VERSION 5.7 ;
  NOWIREEXTENSIONATPIN ON ;
  DIVIDERCHAR "/" ;
  BUSBITCHARS "[]" ;
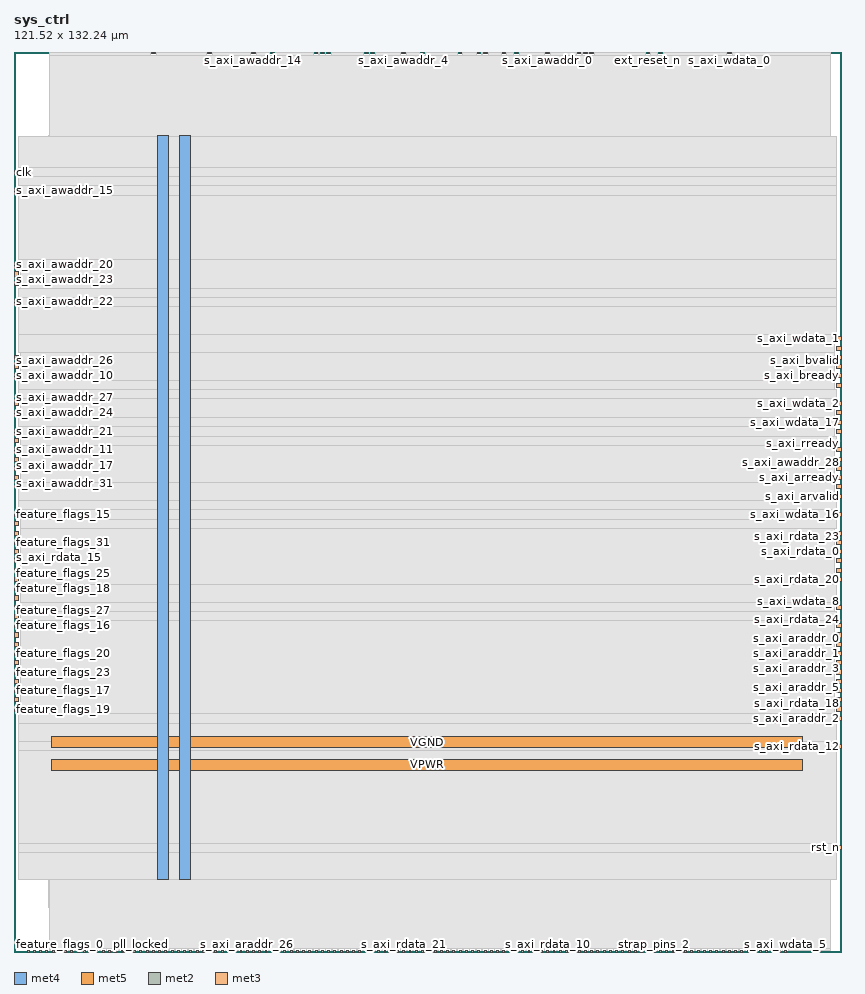
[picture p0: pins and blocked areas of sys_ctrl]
MACRO sys_ctrl
  CLASS BLOCK ;
  FOREIGN sys_ctrl ;
  ORIGIN 0.000 0.000 ;
  SIZE 121.520 BY 132.240 ;
  PIN VGND
    DIRECTION INOUT ;
    USE GROUND ;
    PORT
      LAYER met4 ;
        RECT 24.340 10.640 25.940 119.920 ;
    END
    PORT
      LAYER met5 ;
        RECT 5.520 30.030 115.920 31.630 ;
    END
  END VGND
  PIN VPWR
    DIRECTION INOUT ;
    USE POWER ;
    PORT
      LAYER met4 ;
        RECT 21.040 10.640 22.640 119.920 ;
    END
    PORT
      LAYER met5 ;
        RECT 5.520 26.730 115.920 28.330 ;
    END
  END VPWR
  PIN boot_mode_0
    DIRECTION INPUT ;
    USE SIGNAL ;
    PORT
      LAYER met2 ;
        RECT 2.850 0.000 3.130 0.280 ;
    END
  END boot_mode_0
  PIN boot_mode_1
    DIRECTION INPUT ;
    USE SIGNAL ;
    PORT
      LAYER met2 ;
        RECT 3.770 0.000 4.050 0.280 ;
    END
  END boot_mode_1
  PIN clk
    DIRECTION INPUT ;
    USE SIGNAL ;
    ANTENNAGATEAREA 1.286700 ;
    ANTENNADIFFAREA 0.434700 ;
    PORT
      LAYER met3 ;
        RECT 0.000 114.280 0.600 114.880 ;
    END
  END clk
  PIN ext_reset_n
    DIRECTION INPUT ;
    USE SIGNAL ;
    ANTENNAGATEAREA 0.647700 ;
    ANTENNADIFFAREA 0.434700 ;
    PORT
      LAYER met2 ;
        RECT 93.010 131.960 93.290 132.240 ;
    END
  END ext_reset_n
  PIN feature_flags_0
    DIRECTION OUTPUT ;
    USE SIGNAL ;
    PORT
      LAYER met2 ;
        RECT 4.690 0.000 4.970 0.280 ;
    END
  END feature_flags_0
  PIN feature_flags_1
    DIRECTION OUTPUT ;
    USE SIGNAL ;
    PORT
      LAYER met2 ;
        RECT 5.610 0.000 5.890 0.280 ;
    END
  END feature_flags_1
  PIN feature_flags_10
    DIRECTION OUTPUT ;
    USE SIGNAL ;
    PORT
      LAYER met2 ;
        RECT 6.530 0.000 6.810 0.280 ;
    END
  END feature_flags_10
  PIN feature_flags_11
    DIRECTION OUTPUT ;
    USE SIGNAL ;
    PORT
      LAYER met2 ;
        RECT 7.450 0.000 7.730 0.280 ;
    END
  END feature_flags_11
  PIN feature_flags_12
    DIRECTION OUTPUT ;
    USE SIGNAL ;
    PORT
      LAYER met2 ;
        RECT 8.370 0.000 8.650 0.280 ;
    END
  END feature_flags_12
  PIN feature_flags_13
    DIRECTION OUTPUT ;
    USE SIGNAL ;
    PORT
      LAYER met2 ;
        RECT 9.290 0.000 9.570 0.280 ;
    END
  END feature_flags_13
  PIN feature_flags_14
    DIRECTION OUTPUT ;
    USE SIGNAL ;
    PORT
      LAYER met2 ;
        RECT 10.210 0.000 10.490 0.280 ;
    END
  END feature_flags_14
  PIN feature_flags_15
    DIRECTION OUTPUT ;
    USE SIGNAL ;
    ANTENNAGATEAREA 0.434700 ;
    ANTENNADIFFAREA 0.775300 ;
    PORT
      LAYER met3 ;
        RECT 0.000 63.960 0.600 64.560 ;
    END
  END feature_flags_15
  PIN feature_flags_16
    DIRECTION OUTPUT ;
    USE SIGNAL ;
    ANTENNAGATEAREA 0.434700 ;
    ANTENNADIFFAREA 0.775300 ;
    PORT
      LAYER met3 ;
        RECT 0.000 47.640 0.600 48.240 ;
    END
  END feature_flags_16
  PIN feature_flags_17
    DIRECTION OUTPUT ;
    USE SIGNAL ;
    ANTENNAGATEAREA 0.434700 ;
    ANTENNADIFFAREA 0.775300 ;
    PORT
      LAYER met3 ;
        RECT 0.000 38.120 0.600 38.720 ;
    END
  END feature_flags_17
  PIN feature_flags_18
    DIRECTION OUTPUT ;
    USE SIGNAL ;
    ANTENNAGATEAREA 0.434700 ;
    ANTENNADIFFAREA 0.775300 ;
    PORT
      LAYER met3 ;
        RECT 0.000 53.080 0.600 53.680 ;
    END
  END feature_flags_18
  PIN feature_flags_19
    DIRECTION OUTPUT ;
    USE SIGNAL ;
    ANTENNAGATEAREA 0.434700 ;
    ANTENNADIFFAREA 0.775300 ;
    PORT
      LAYER met3 ;
        RECT 0.000 35.400 0.600 36.000 ;
    END
  END feature_flags_19
  PIN feature_flags_2
    DIRECTION OUTPUT ;
    USE SIGNAL ;
    PORT
      LAYER met2 ;
        RECT 11.130 0.000 11.410 0.280 ;
    END
  END feature_flags_2
  PIN feature_flags_20
    DIRECTION OUTPUT ;
    USE SIGNAL ;
    ANTENNAGATEAREA 0.434700 ;
    ANTENNADIFFAREA 0.775300 ;
    PORT
      LAYER met3 ;
        RECT 0.000 43.560 0.600 44.160 ;
    END
  END feature_flags_20
  PIN feature_flags_21
    DIRECTION OUTPUT ;
    USE SIGNAL ;
    ANTENNAGATEAREA 0.434700 ;
    ANTENNADIFFAREA 0.775300 ;
    PORT
      LAYER met3 ;
        RECT 0.000 55.800 0.600 56.400 ;
    END
  END feature_flags_21
  PIN feature_flags_22
    DIRECTION OUTPUT ;
    USE SIGNAL ;
    ANTENNAGATEAREA 0.434700 ;
    ANTENNADIFFAREA 0.775300 ;
    PORT
      LAYER met3 ;
        RECT 0.000 46.280 0.600 46.880 ;
    END
  END feature_flags_22
  PIN feature_flags_23
    DIRECTION OUTPUT ;
    USE SIGNAL ;
    ANTENNAGATEAREA 0.434700 ;
    ANTENNADIFFAREA 0.775300 ;
    PORT
      LAYER met3 ;
        RECT 0.000 40.840 0.600 41.440 ;
    END
  END feature_flags_23
  PIN feature_flags_24
    DIRECTION OUTPUT ;
    USE SIGNAL ;
    ANTENNAGATEAREA 0.434700 ;
    ANTENNADIFFAREA 0.775300 ;
    PORT
      LAYER met3 ;
        RECT 0.000 57.160 0.600 57.760 ;
    END
  END feature_flags_24
  PIN feature_flags_25
    DIRECTION OUTPUT ;
    USE SIGNAL ;
    ANTENNAGATEAREA 0.434700 ;
    ANTENNADIFFAREA 0.775300 ;
    PORT
      LAYER met3 ;
        RECT 0.000 54.440 0.600 55.040 ;
    END
  END feature_flags_25
  PIN feature_flags_26
    DIRECTION OUTPUT ;
    USE SIGNAL ;
    ANTENNAGATEAREA 0.434700 ;
    ANTENNADIFFAREA 0.775300 ;
    PORT
      LAYER met3 ;
        RECT 0.000 44.920 0.600 45.520 ;
    END
  END feature_flags_26
  PIN feature_flags_27
    DIRECTION OUTPUT ;
    USE SIGNAL ;
    ANTENNAGATEAREA 0.434700 ;
    ANTENNADIFFAREA 0.775300 ;
    PORT
      LAYER met3 ;
        RECT 0.000 49.000 0.600 49.600 ;
    END
  END feature_flags_27
  PIN feature_flags_28
    DIRECTION OUTPUT ;
    USE SIGNAL ;
    ANTENNAGATEAREA 0.434700 ;
    ANTENNADIFFAREA 0.775300 ;
    PORT
      LAYER met3 ;
        RECT 0.000 51.720 0.600 52.320 ;
    END
  END feature_flags_28
  PIN feature_flags_29
    DIRECTION OUTPUT ;
    USE SIGNAL ;
    ANTENNAGATEAREA 0.434700 ;
    ANTENNADIFFAREA 0.775300 ;
    PORT
      LAYER met3 ;
        RECT 0.000 39.480 0.600 40.080 ;
    END
  END feature_flags_29
  PIN feature_flags_3
    DIRECTION OUTPUT ;
    USE SIGNAL ;
    PORT
      LAYER met2 ;
        RECT 12.050 0.000 12.330 0.280 ;
    END
  END feature_flags_3
  PIN feature_flags_30
    DIRECTION OUTPUT ;
    USE SIGNAL ;
    ANTENNAGATEAREA 0.434700 ;
    ANTENNADIFFAREA 0.775300 ;
    PORT
      LAYER met3 ;
        RECT 0.000 42.200 0.600 42.800 ;
    END
  END feature_flags_30
  PIN feature_flags_31
    DIRECTION OUTPUT ;
    USE SIGNAL ;
    ANTENNAGATEAREA 0.434700 ;
    ANTENNADIFFAREA 0.775300 ;
    PORT
      LAYER met3 ;
        RECT 0.000 59.880 0.600 60.480 ;
    END
  END feature_flags_31
  PIN feature_flags_4
    DIRECTION OUTPUT ;
    USE SIGNAL ;
    PORT
      LAYER met2 ;
        RECT 12.970 0.000 13.250 0.280 ;
    END
  END feature_flags_4
  PIN feature_flags_5
    DIRECTION OUTPUT ;
    USE SIGNAL ;
    PORT
      LAYER met2 ;
        RECT 13.890 0.000 14.170 0.280 ;
    END
  END feature_flags_5
  PIN feature_flags_6
    DIRECTION OUTPUT ;
    USE SIGNAL ;
    PORT
      LAYER met2 ;
        RECT 14.810 0.000 15.090 0.280 ;
    END
  END feature_flags_6
  PIN feature_flags_7
    DIRECTION OUTPUT ;
    USE SIGNAL ;
    PORT
      LAYER met2 ;
        RECT 15.730 0.000 16.010 0.280 ;
    END
  END feature_flags_7
  PIN feature_flags_8
    DIRECTION OUTPUT ;
    USE SIGNAL ;
    PORT
      LAYER met2 ;
        RECT 16.650 0.000 16.930 0.280 ;
    END
  END feature_flags_8
  PIN feature_flags_9
    DIRECTION OUTPUT ;
    USE SIGNAL ;
    PORT
      LAYER met2 ;
        RECT 17.570 0.000 17.850 0.280 ;
    END
  END feature_flags_9
  PIN lockup_reset
    DIRECTION INPUT ;
    USE SIGNAL ;
    ANTENNAGATEAREA 0.647700 ;
    ANTENNADIFFAREA 0.434700 ;
    PORT
      LAYER met2 ;
        RECT 94.850 131.960 95.130 132.240 ;
    END
  END lockup_reset
  PIN pll_locked
    DIRECTION INPUT ;
    USE SIGNAL ;
    PORT
      LAYER met2 ;
        RECT 18.490 0.000 18.770 0.280 ;
    END
  END pll_locked
  PIN ref_clk_ok
    DIRECTION INPUT ;
    USE SIGNAL ;
    PORT
      LAYER met2 ;
        RECT 19.410 0.000 19.690 0.280 ;
    END
  END ref_clk_ok
  PIN rst_n
    DIRECTION INPUT ;
    USE SIGNAL ;
    ANTENNAGATEAREA 0.647700 ;
    ANTENNADIFFAREA 0.434700 ;
    PORT
      LAYER met3 ;
        RECT 120.920 15.000 121.520 15.600 ;
    END
  END rst_n
  PIN s_axi_araddr_0
    DIRECTION INPUT ;
    USE SIGNAL ;
    ANTENNAGATEAREA 0.647700 ;
    ANTENNADIFFAREA 0.434700 ;
    PORT
      LAYER met3 ;
        RECT 120.920 44.920 121.520 45.520 ;
    END
  END s_axi_araddr_0
  PIN s_axi_araddr_1
    DIRECTION INPUT ;
    USE SIGNAL ;
    ANTENNAGATEAREA 0.647700 ;
    ANTENNADIFFAREA 0.434700 ;
    PORT
      LAYER met3 ;
        RECT 120.920 43.560 121.520 44.160 ;
    END
  END s_axi_araddr_1
  PIN s_axi_araddr_10
    DIRECTION INPUT ;
    USE SIGNAL ;
    PORT
      LAYER met2 ;
        RECT 20.330 0.000 20.610 0.280 ;
    END
  END s_axi_araddr_10
  PIN s_axi_araddr_11
    DIRECTION INPUT ;
    USE SIGNAL ;
    PORT
      LAYER met2 ;
        RECT 21.250 0.000 21.530 0.280 ;
    END
  END s_axi_araddr_11
  PIN s_axi_araddr_12
    DIRECTION INPUT ;
    USE SIGNAL ;
    PORT
      LAYER met2 ;
        RECT 22.170 0.000 22.450 0.280 ;
    END
  END s_axi_araddr_12
  PIN s_axi_araddr_13
    DIRECTION INPUT ;
    USE SIGNAL ;
    PORT
      LAYER met2 ;
        RECT 23.090 0.000 23.370 0.280 ;
    END
  END s_axi_araddr_13
  PIN s_axi_araddr_14
    DIRECTION INPUT ;
    USE SIGNAL ;
    PORT
      LAYER met2 ;
        RECT 24.010 0.000 24.290 0.280 ;
    END
  END s_axi_araddr_14
  PIN s_axi_araddr_15
    DIRECTION INPUT ;
    USE SIGNAL ;
    PORT
      LAYER met2 ;
        RECT 74.610 0.000 74.890 0.280 ;
    END
  END s_axi_araddr_15
  PIN s_axi_araddr_16
    DIRECTION INPUT ;
    USE SIGNAL ;
    PORT
      LAYER met2 ;
        RECT 24.930 0.000 25.210 0.280 ;
    END
  END s_axi_araddr_16
  PIN s_axi_araddr_17
    DIRECTION INPUT ;
    USE SIGNAL ;
    PORT
      LAYER met2 ;
        RECT 25.850 0.000 26.130 0.280 ;
    END
  END s_axi_araddr_17
  PIN s_axi_araddr_18
    DIRECTION INPUT ;
    USE SIGNAL ;
    PORT
      LAYER met2 ;
        RECT 26.770 0.000 27.050 0.280 ;
    END
  END s_axi_araddr_18
  PIN s_axi_araddr_19
    DIRECTION INPUT ;
    USE SIGNAL ;
    PORT
      LAYER met2 ;
        RECT 27.690 0.000 27.970 0.280 ;
    END
  END s_axi_araddr_19
  PIN s_axi_araddr_2
    DIRECTION INPUT ;
    USE SIGNAL ;
    ANTENNAGATEAREA 0.647700 ;
    ANTENNADIFFAREA 0.434700 ;
    PORT
      LAYER met3 ;
        RECT 120.920 34.040 121.520 34.640 ;
    END
  END s_axi_araddr_2
  PIN s_axi_araddr_20
    DIRECTION INPUT ;
    USE SIGNAL ;
    PORT
      LAYER met2 ;
        RECT 28.610 0.000 28.890 0.280 ;
    END
  END s_axi_araddr_20
  PIN s_axi_araddr_21
    DIRECTION INPUT ;
    USE SIGNAL ;
    PORT
      LAYER met2 ;
        RECT 29.530 0.000 29.810 0.280 ;
    END
  END s_axi_araddr_21
  PIN s_axi_araddr_22
    DIRECTION INPUT ;
    USE SIGNAL ;
    PORT
      LAYER met2 ;
        RECT 30.450 0.000 30.730 0.280 ;
    END
  END s_axi_araddr_22
  PIN s_axi_araddr_23
    DIRECTION INPUT ;
    USE SIGNAL ;
    PORT
      LAYER met2 ;
        RECT 31.370 0.000 31.650 0.280 ;
    END
  END s_axi_araddr_23
  PIN s_axi_araddr_24
    DIRECTION INPUT ;
    USE SIGNAL ;
    PORT
      LAYER met2 ;
        RECT 32.290 0.000 32.570 0.280 ;
    END
  END s_axi_araddr_24
  PIN s_axi_araddr_25
    DIRECTION INPUT ;
    USE SIGNAL ;
    PORT
      LAYER met2 ;
        RECT 33.210 0.000 33.490 0.280 ;
    END
  END s_axi_araddr_25
  PIN s_axi_araddr_26
    DIRECTION INPUT ;
    USE SIGNAL ;
    PORT
      LAYER met2 ;
        RECT 34.130 0.000 34.410 0.280 ;
    END
  END s_axi_araddr_26
  PIN s_axi_araddr_27
    DIRECTION INPUT ;
    USE SIGNAL ;
    PORT
      LAYER met2 ;
        RECT 35.050 0.000 35.330 0.280 ;
    END
  END s_axi_araddr_27
  PIN s_axi_araddr_28
    DIRECTION INPUT ;
    USE SIGNAL ;
    PORT
      LAYER met2 ;
        RECT 35.970 0.000 36.250 0.280 ;
    END
  END s_axi_araddr_28
  PIN s_axi_araddr_29
    DIRECTION INPUT ;
    USE SIGNAL ;
    PORT
      LAYER met2 ;
        RECT 36.890 0.000 37.170 0.280 ;
    END
  END s_axi_araddr_29
  PIN s_axi_araddr_3
    DIRECTION INPUT ;
    USE SIGNAL ;
    ANTENNAGATEAREA 0.647700 ;
    ANTENNADIFFAREA 0.434700 ;
    PORT
      LAYER met3 ;
        RECT 120.920 42.200 121.520 42.800 ;
    END
  END s_axi_araddr_3
  PIN s_axi_araddr_30
    DIRECTION INPUT ;
    USE SIGNAL ;
    PORT
      LAYER met2 ;
        RECT 37.810 0.000 38.090 0.280 ;
    END
  END s_axi_araddr_30
  PIN s_axi_araddr_31
    DIRECTION INPUT ;
    USE SIGNAL ;
    PORT
      LAYER met2 ;
        RECT 38.730 0.000 39.010 0.280 ;
    END
  END s_axi_araddr_31
  PIN s_axi_araddr_4
    DIRECTION INPUT ;
    USE SIGNAL ;
    ANTENNAGATEAREA 0.647700 ;
    ANTENNADIFFAREA 0.434700 ;
    PORT
      LAYER met3 ;
        RECT 120.920 40.840 121.520 41.440 ;
    END
  END s_axi_araddr_4
  PIN s_axi_araddr_5
    DIRECTION INPUT ;
    USE SIGNAL ;
    ANTENNAGATEAREA 0.647700 ;
    ANTENNADIFFAREA 0.434700 ;
    PORT
      LAYER met3 ;
        RECT 120.920 39.480 121.520 40.080 ;
    END
  END s_axi_araddr_5
  PIN s_axi_araddr_6
    DIRECTION INPUT ;
    USE SIGNAL ;
    ANTENNAGATEAREA 0.647700 ;
    ANTENNADIFFAREA 0.434700 ;
    PORT
      LAYER met3 ;
        RECT 120.920 38.120 121.520 38.720 ;
    END
  END s_axi_araddr_6
  PIN s_axi_araddr_7
    DIRECTION INPUT ;
    USE SIGNAL ;
    ANTENNAGATEAREA 0.647700 ;
    ANTENNADIFFAREA 0.434700 ;
    PORT
      LAYER met3 ;
        RECT 120.920 36.760 121.520 37.360 ;
    END
  END s_axi_araddr_7
  PIN s_axi_araddr_8
    DIRECTION INPUT ;
    USE SIGNAL ;
    PORT
      LAYER met2 ;
        RECT 39.650 0.000 39.930 0.280 ;
    END
  END s_axi_araddr_8
  PIN s_axi_araddr_9
    DIRECTION INPUT ;
    USE SIGNAL ;
    PORT
      LAYER met2 ;
        RECT 40.570 0.000 40.850 0.280 ;
    END
  END s_axi_araddr_9
  PIN s_axi_arready
    DIRECTION OUTPUT ;
    USE SIGNAL ;
    ANTENNAGATEAREA 0.434700 ;
    ANTENNADIFFAREA 1.137600 ;
    PORT
      LAYER met3 ;
        RECT 120.920 69.400 121.520 70.000 ;
    END
  END s_axi_arready
  PIN s_axi_arvalid
    DIRECTION INPUT ;
    USE SIGNAL ;
    ANTENNAGATEAREA 0.647700 ;
    ANTENNADIFFAREA 0.434700 ;
    PORT
      LAYER met3 ;
        RECT 120.920 66.680 121.520 67.280 ;
    END
  END s_axi_arvalid
  PIN s_axi_awaddr_0
    DIRECTION INPUT ;
    USE SIGNAL ;
    ANTENNAGATEAREA 0.647700 ;
    ANTENNADIFFAREA 0.434700 ;
    PORT
      LAYER met2 ;
        RECT 78.290 131.960 78.570 132.240 ;
    END
  END s_axi_awaddr_0
  PIN s_axi_awaddr_1
    DIRECTION INPUT ;
    USE SIGNAL ;
    ANTENNAGATEAREA 0.647700 ;
    ANTENNADIFFAREA 0.434700 ;
    PORT
      LAYER met2 ;
        RECT 69.090 131.960 69.370 132.240 ;
    END
  END s_axi_awaddr_1
  PIN s_axi_awaddr_10
    DIRECTION INPUT ;
    USE SIGNAL ;
    ANTENNAGATEAREA 0.647700 ;
    ANTENNADIFFAREA 0.434700 ;
    PORT
      LAYER met3 ;
        RECT 0.000 84.360 0.600 84.960 ;
    END
  END s_axi_awaddr_10
  PIN s_axi_awaddr_11
    DIRECTION INPUT ;
    USE SIGNAL ;
    ANTENNAGATEAREA 0.647700 ;
    ANTENNADIFFAREA 0.434700 ;
    PORT
      LAYER met3 ;
        RECT 0.000 73.480 0.600 74.080 ;
    END
  END s_axi_awaddr_11
  PIN s_axi_awaddr_12
    DIRECTION INPUT ;
    USE SIGNAL ;
    ANTENNAGATEAREA 0.647700 ;
    ANTENNADIFFAREA 0.434700 ;
    PORT
      LAYER met2 ;
        RECT 45.170 131.960 45.450 132.240 ;
    END
  END s_axi_awaddr_12
  PIN s_axi_awaddr_13
    DIRECTION INPUT ;
    USE SIGNAL ;
    ANTENNAGATEAREA 0.647700 ;
    ANTENNADIFFAREA 0.434700 ;
    PORT
      LAYER met2 ;
        RECT 52.530 131.960 52.810 132.240 ;
    END
  END s_axi_awaddr_13
  PIN s_axi_awaddr_14
    DIRECTION INPUT ;
    USE SIGNAL ;
    ANTENNAGATEAREA 0.647700 ;
    ANTENNADIFFAREA 0.434700 ;
    PORT
      LAYER met2 ;
        RECT 35.050 131.960 35.330 132.240 ;
    END
  END s_axi_awaddr_14
  PIN s_axi_awaddr_15
    DIRECTION INPUT ;
    USE SIGNAL ;
    ANTENNAGATEAREA 0.647700 ;
    ANTENNADIFFAREA 0.434700 ;
    PORT
      LAYER met3 ;
        RECT 0.000 111.560 0.600 112.160 ;
    END
  END s_axi_awaddr_15
  PIN s_axi_awaddr_16
    DIRECTION INPUT ;
    USE SIGNAL ;
    ANTENNAGATEAREA 0.647700 ;
    ANTENNADIFFAREA 0.434700 ;
    PORT
      LAYER met2 ;
        RECT 44.250 131.960 44.530 132.240 ;
    END
  END s_axi_awaddr_16
  PIN s_axi_awaddr_17
    DIRECTION INPUT ;
    USE SIGNAL ;
    ANTENNAGATEAREA 0.647700 ;
    ANTENNADIFFAREA 0.434700 ;
    PORT
      LAYER met3 ;
        RECT 0.000 72.120 0.600 72.720 ;
    END
  END s_axi_awaddr_17
  PIN s_axi_awaddr_18
    DIRECTION INPUT ;
    USE SIGNAL ;
    ANTENNAGATEAREA 0.647700 ;
    ANTENNADIFFAREA 0.434700 ;
    PORT
      LAYER met2 ;
        RECT 28.610 131.960 28.890 132.240 ;
    END
  END s_axi_awaddr_18
  PIN s_axi_awaddr_19
    DIRECTION INPUT ;
    USE SIGNAL ;
    ANTENNAGATEAREA 0.647700 ;
    ANTENNADIFFAREA 0.434700 ;
    PORT
      LAYER met2 ;
        RECT 37.810 131.960 38.090 132.240 ;
    END
  END s_axi_awaddr_19
  PIN s_axi_awaddr_2
    DIRECTION INPUT ;
    USE SIGNAL ;
    ANTENNAGATEAREA 0.647700 ;
    ANTENNADIFFAREA 0.434700 ;
    PORT
      LAYER met2 ;
        RECT 73.690 131.960 73.970 132.240 ;
    END
  END s_axi_awaddr_2
  PIN s_axi_awaddr_20
    DIRECTION INPUT ;
    USE SIGNAL ;
    ANTENNAGATEAREA 0.647700 ;
    ANTENNADIFFAREA 0.434700 ;
    PORT
      LAYER met3 ;
        RECT 0.000 100.680 0.600 101.280 ;
    END
  END s_axi_awaddr_20
  PIN s_axi_awaddr_21
    DIRECTION INPUT ;
    USE SIGNAL ;
    ANTENNAGATEAREA 0.647700 ;
    ANTENNADIFFAREA 0.434700 ;
    PORT
      LAYER met3 ;
        RECT 0.000 76.200 0.600 76.800 ;
    END
  END s_axi_awaddr_21
  PIN s_axi_awaddr_22
    DIRECTION INPUT ;
    USE SIGNAL ;
    ANTENNAGATEAREA 0.647700 ;
    ANTENNADIFFAREA 0.434700 ;
    PORT
      LAYER met3 ;
        RECT 0.000 95.240 0.600 95.840 ;
    END
  END s_axi_awaddr_22
  PIN s_axi_awaddr_23
    DIRECTION INPUT ;
    USE SIGNAL ;
    ANTENNAGATEAREA 0.647700 ;
    ANTENNADIFFAREA 0.434700 ;
    PORT
      LAYER met3 ;
        RECT 0.000 99.320 0.600 99.920 ;
    END
  END s_axi_awaddr_23
  PIN s_axi_awaddr_24
    DIRECTION INPUT ;
    USE SIGNAL ;
    ANTENNAGATEAREA 0.647700 ;
    ANTENNADIFFAREA 0.434700 ;
    PORT
      LAYER met3 ;
        RECT 0.000 78.920 0.600 79.520 ;
    END
  END s_axi_awaddr_24
  PIN s_axi_awaddr_25
    DIRECTION INPUT ;
    USE SIGNAL ;
    ANTENNAGATEAREA 0.647700 ;
    ANTENNADIFFAREA 0.434700 ;
    PORT
      LAYER met2 ;
        RECT 20.330 131.960 20.610 132.240 ;
    END
  END s_axi_awaddr_25
  PIN s_axi_awaddr_26
    DIRECTION INPUT ;
    USE SIGNAL ;
    ANTENNAGATEAREA 0.647700 ;
    ANTENNADIFFAREA 0.434700 ;
    PORT
      LAYER met3 ;
        RECT 0.000 85.720 0.600 86.320 ;
    END
  END s_axi_awaddr_26
  PIN s_axi_awaddr_27
    DIRECTION INPUT ;
    USE SIGNAL ;
    ANTENNAGATEAREA 0.647700 ;
    ANTENNADIFFAREA 0.434700 ;
    PORT
      LAYER met3 ;
        RECT 0.000 80.280 0.600 80.880 ;
    END
  END s_axi_awaddr_27
  PIN s_axi_awaddr_28
    DIRECTION INPUT ;
    USE SIGNAL ;
    ANTENNAGATEAREA 0.647700 ;
    ANTENNADIFFAREA 0.434700 ;
    PORT
      LAYER met3 ;
        RECT 120.920 70.760 121.520 71.360 ;
    END
  END s_axi_awaddr_28
  PIN s_axi_awaddr_29
    DIRECTION INPUT ;
    USE SIGNAL ;
    ANTENNAGATEAREA 0.647700 ;
    ANTENNADIFFAREA 0.434700 ;
    PORT
      LAYER met3 ;
        RECT 0.000 70.760 0.600 71.360 ;
    END
  END s_axi_awaddr_29
  PIN s_axi_awaddr_3
    DIRECTION INPUT ;
    USE SIGNAL ;
    ANTENNAGATEAREA 0.647700 ;
    ANTENNADIFFAREA 0.434700 ;
    PORT
      LAYER met2 ;
        RECT 68.170 131.960 68.450 132.240 ;
    END
  END s_axi_awaddr_3
  PIN s_axi_awaddr_30
    DIRECTION INPUT ;
    USE SIGNAL ;
    ANTENNAGATEAREA 0.647700 ;
    ANTENNADIFFAREA 0.434700 ;
    PORT
      LAYER met3 ;
        RECT 0.000 74.840 0.600 75.440 ;
    END
  END s_axi_awaddr_30
  PIN s_axi_awaddr_31
    DIRECTION INPUT ;
    USE SIGNAL ;
    ANTENNAGATEAREA 0.647700 ;
    ANTENNADIFFAREA 0.434700 ;
    PORT
      LAYER met3 ;
        RECT 0.000 69.400 0.600 70.000 ;
    END
  END s_axi_awaddr_31
  PIN s_axi_awaddr_4
    DIRECTION INPUT ;
    USE SIGNAL ;
    ANTENNAGATEAREA 0.647700 ;
    ANTENNADIFFAREA 0.434700 ;
    PORT
      LAYER met2 ;
        RECT 57.130 131.960 57.410 132.240 ;
    END
  END s_axi_awaddr_4
  PIN s_axi_awaddr_5
    DIRECTION INPUT ;
    USE SIGNAL ;
    ANTENNAGATEAREA 0.647700 ;
    ANTENNADIFFAREA 0.434700 ;
    PORT
      LAYER met2 ;
        RECT 59.890 131.960 60.170 132.240 ;
    END
  END s_axi_awaddr_5
  PIN s_axi_awaddr_6
    DIRECTION INPUT ;
    USE SIGNAL ;
    ANTENNAGATEAREA 0.647700 ;
    ANTENNADIFFAREA 0.434700 ;
    PORT
      LAYER met2 ;
        RECT 46.090 131.960 46.370 132.240 ;
    END
  END s_axi_awaddr_6
  PIN s_axi_awaddr_7
    DIRECTION INPUT ;
    USE SIGNAL ;
    ANTENNAGATEAREA 0.647700 ;
    ANTENNADIFFAREA 0.434700 ;
    PORT
      LAYER met2 ;
        RECT 51.610 131.960 51.890 132.240 ;
    END
  END s_axi_awaddr_7
  PIN s_axi_awaddr_8
    DIRECTION INPUT ;
    USE SIGNAL ;
    ANTENNAGATEAREA 0.647700 ;
    ANTENNADIFFAREA 0.434700 ;
    PORT
      LAYER met3 ;
        RECT 0.000 97.960 0.600 98.560 ;
    END
  END s_axi_awaddr_8
  PIN s_axi_awaddr_9
    DIRECTION INPUT ;
    USE SIGNAL ;
    ANTENNAGATEAREA 0.647700 ;
    ANTENNADIFFAREA 0.434700 ;
    PORT
      LAYER met3 ;
        RECT 0.000 87.080 0.600 87.680 ;
    END
  END s_axi_awaddr_9
  PIN s_axi_awready
    DIRECTION OUTPUT ;
    USE SIGNAL ;
    PORT
      LAYER met2 ;
        RECT 41.490 0.000 41.770 0.280 ;
    END
  END s_axi_awready
  PIN s_axi_awvalid
    DIRECTION INPUT ;
    USE SIGNAL ;
    ANTENNAGATEAREA 0.647700 ;
    ANTENNADIFFAREA 0.434700 ;
    PORT
      LAYER met2 ;
        RECT 65.410 131.960 65.690 132.240 ;
    END
  END s_axi_awvalid
  PIN s_axi_bready
    DIRECTION INPUT ;
    USE SIGNAL ;
    ANTENNAGATEAREA 0.647700 ;
    ANTENNADIFFAREA 0.434700 ;
    PORT
      LAYER met3 ;
        RECT 120.920 84.360 121.520 84.960 ;
    END
  END s_axi_bready
  PIN s_axi_bresp_0
    DIRECTION OUTPUT ;
    USE SIGNAL ;
    PORT
      LAYER met2 ;
        RECT 1.930 0.000 2.210 0.280 ;
    END
  END s_axi_bresp_0
  PIN s_axi_bresp_1
    DIRECTION OUTPUT ;
    USE SIGNAL ;
    PORT
      LAYER met2 ;
        RECT 43.330 0.000 43.610 0.280 ;
    END
  END s_axi_bresp_1
  PIN s_axi_bvalid
    DIRECTION OUTPUT ;
    USE SIGNAL ;
    ANTENNAGATEAREA 0.434700 ;
    ANTENNADIFFAREA 1.137600 ;
    PORT
      LAYER met3 ;
        RECT 120.920 85.720 121.520 86.320 ;
    END
  END s_axi_bvalid
  PIN s_axi_rdata_0
    DIRECTION OUTPUT ;
    USE SIGNAL ;
    ANTENNAGATEAREA 0.434700 ;
    ANTENNADIFFAREA 1.137600 ;
    PORT
      LAYER met3 ;
        RECT 120.920 58.520 121.520 59.120 ;
    END
  END s_axi_rdata_0
  PIN s_axi_rdata_1
    DIRECTION OUTPUT ;
    USE SIGNAL ;
    ANTENNAGATEAREA 0.434700 ;
    ANTENNADIFFAREA 1.137600 ;
    PORT
      LAYER met2 ;
        RECT 55.290 0.000 55.570 0.280 ;
    END
  END s_axi_rdata_1
  PIN s_axi_rdata_10
    DIRECTION OUTPUT ;
    USE SIGNAL ;
    ANTENNAGATEAREA 0.434700 ;
    ANTENNADIFFAREA 1.137600 ;
    PORT
      LAYER met2 ;
        RECT 78.290 0.000 78.570 0.280 ;
    END
  END s_axi_rdata_10
  PIN s_axi_rdata_11
    DIRECTION OUTPUT ;
    USE SIGNAL ;
    ANTENNAGATEAREA 0.434700 ;
    ANTENNADIFFAREA 1.137600 ;
    PORT
      LAYER met2 ;
        RECT 54.370 0.000 54.650 0.280 ;
    END
  END s_axi_rdata_11
  PIN s_axi_rdata_12
    DIRECTION OUTPUT ;
    USE SIGNAL ;
    ANTENNAGATEAREA 0.434700 ;
    ANTENNADIFFAREA 1.137600 ;
    PORT
      LAYER met3 ;
        RECT 120.920 29.960 121.520 30.560 ;
    END
  END s_axi_rdata_12
  PIN s_axi_rdata_13
    DIRECTION OUTPUT ;
    USE SIGNAL ;
    ANTENNAGATEAREA 0.434700 ;
    ANTENNADIFFAREA 1.137600 ;
    PORT
      LAYER met2 ;
        RECT 52.530 0.000 52.810 0.280 ;
    END
  END s_axi_rdata_13
  PIN s_axi_rdata_14
    DIRECTION OUTPUT ;
    USE SIGNAL ;
    ANTENNAGATEAREA 0.434700 ;
    ANTENNADIFFAREA 1.137600 ;
    PORT
      LAYER met2 ;
        RECT 51.610 0.000 51.890 0.280 ;
    END
  END s_axi_rdata_14
  PIN s_axi_rdata_15
    DIRECTION OUTPUT ;
    USE SIGNAL ;
    ANTENNAGATEAREA 0.434700 ;
    ANTENNADIFFAREA 1.137600 ;
    PORT
      LAYER met3 ;
        RECT 0.000 58.520 0.600 59.120 ;
    END
  END s_axi_rdata_15
  PIN s_axi_rdata_16
    DIRECTION OUTPUT ;
    USE SIGNAL ;
    ANTENNAGATEAREA 0.434700 ;
    ANTENNADIFFAREA 1.137600 ;
    PORT
      LAYER met3 ;
        RECT 0.000 62.600 0.600 63.200 ;
    END
  END s_axi_rdata_16
  PIN s_axi_rdata_17
    DIRECTION OUTPUT ;
    USE SIGNAL ;
    ANTENNAGATEAREA 0.434700 ;
    ANTENNADIFFAREA 1.137600 ;
    PORT
      LAYER met3 ;
        RECT 120.920 61.240 121.520 61.840 ;
    END
  END s_axi_rdata_17
  PIN s_axi_rdata_18
    DIRECTION OUTPUT ;
    USE SIGNAL ;
    ANTENNAGATEAREA 0.434700 ;
    ANTENNADIFFAREA 1.137600 ;
    PORT
      LAYER met3 ;
        RECT 120.920 35.400 121.520 36.000 ;
    END
  END s_axi_rdata_18
  PIN s_axi_rdata_19
    DIRECTION OUTPUT ;
    USE SIGNAL ;
    ANTENNAGATEAREA 0.434700 ;
    ANTENNADIFFAREA 1.137600 ;
    PORT
      LAYER met2 ;
        RECT 56.210 0.000 56.490 0.280 ;
    END
  END s_axi_rdata_19
  PIN s_axi_rdata_2
    DIRECTION OUTPUT ;
    USE SIGNAL ;
    ANTENNAGATEAREA 0.434700 ;
    ANTENNADIFFAREA 1.137600 ;
    PORT
      LAYER met2 ;
        RECT 67.250 0.000 67.530 0.280 ;
    END
  END s_axi_rdata_2
  PIN s_axi_rdata_20
    DIRECTION OUTPUT ;
    USE SIGNAL ;
    ANTENNAGATEAREA 0.434700 ;
    ANTENNADIFFAREA 1.137600 ;
    PORT
      LAYER met3 ;
        RECT 120.920 54.440 121.520 55.040 ;
    END
  END s_axi_rdata_20
  PIN s_axi_rdata_21
    DIRECTION OUTPUT ;
    USE SIGNAL ;
    ANTENNAGATEAREA 0.434700 ;
    ANTENNADIFFAREA 1.137600 ;
    PORT
      LAYER met2 ;
        RECT 57.130 0.000 57.410 0.280 ;
    END
  END s_axi_rdata_21
  PIN s_axi_rdata_22
    DIRECTION OUTPUT ;
    USE SIGNAL ;
    ANTENNAGATEAREA 0.434700 ;
    ANTENNADIFFAREA 1.137600 ;
    PORT
      LAYER met3 ;
        RECT 120.920 57.160 121.520 57.760 ;
    END
  END s_axi_rdata_22
  PIN s_axi_rdata_23
    DIRECTION OUTPUT ;
    USE SIGNAL ;
    ANTENNAGATEAREA 0.434700 ;
    ANTENNADIFFAREA 1.137600 ;
    PORT
      LAYER met3 ;
        RECT 120.920 59.880 121.520 60.480 ;
    END
  END s_axi_rdata_23
  PIN s_axi_rdata_24
    DIRECTION OUTPUT ;
    USE SIGNAL ;
    ANTENNAGATEAREA 0.434700 ;
    ANTENNADIFFAREA 1.137600 ;
    PORT
      LAYER met3 ;
        RECT 120.920 47.640 121.520 48.240 ;
    END
  END s_axi_rdata_24
  PIN s_axi_rdata_25
    DIRECTION OUTPUT ;
    USE SIGNAL ;
    ANTENNAGATEAREA 0.434700 ;
    ANTENNADIFFAREA 1.137600 ;
    PORT
      LAYER met2 ;
        RECT 80.130 0.000 80.410 0.280 ;
    END
  END s_axi_rdata_25
  PIN s_axi_rdata_26
    DIRECTION OUTPUT ;
    USE SIGNAL ;
    ANTENNAGATEAREA 0.434700 ;
    ANTENNADIFFAREA 1.137600 ;
    PORT
      LAYER met2 ;
        RECT 65.410 0.000 65.690 0.280 ;
    END
  END s_axi_rdata_26
  PIN s_axi_rdata_27
    DIRECTION OUTPUT ;
    USE SIGNAL ;
    ANTENNAGATEAREA 0.434700 ;
    ANTENNADIFFAREA 1.137600 ;
    PORT
      LAYER met2 ;
        RECT 58.050 0.000 58.330 0.280 ;
    END
  END s_axi_rdata_27
  PIN s_axi_rdata_28
    DIRECTION OUTPUT ;
    USE SIGNAL ;
    ANTENNAGATEAREA 0.434700 ;
    ANTENNADIFFAREA 1.137600 ;
    PORT
      LAYER met3 ;
        RECT 120.920 46.280 121.520 46.880 ;
    END
  END s_axi_rdata_28
  PIN s_axi_rdata_29
    DIRECTION OUTPUT ;
    USE SIGNAL ;
    ANTENNAGATEAREA 0.434700 ;
    ANTENNADIFFAREA 1.137600 ;
    PORT
      LAYER met2 ;
        RECT 81.050 0.000 81.330 0.280 ;
    END
  END s_axi_rdata_29
  PIN s_axi_rdata_3
    DIRECTION OUTPUT ;
    USE SIGNAL ;
    ANTENNAGATEAREA 0.434700 ;
    ANTENNADIFFAREA 1.137600 ;
    PORT
      LAYER met2 ;
        RECT 68.170 0.000 68.450 0.280 ;
    END
  END s_axi_rdata_3
  PIN s_axi_rdata_30
    DIRECTION OUTPUT ;
    USE SIGNAL ;
    ANTENNAGATEAREA 0.434700 ;
    ANTENNADIFFAREA 1.137600 ;
    PORT
      LAYER met3 ;
        RECT 120.920 55.800 121.520 56.400 ;
    END
  END s_axi_rdata_30
  PIN s_axi_rdata_31
    DIRECTION OUTPUT ;
    USE SIGNAL ;
    ANTENNAGATEAREA 0.434700 ;
    ANTENNADIFFAREA 1.137600 ;
    PORT
      LAYER met2 ;
        RECT 44.250 0.000 44.530 0.280 ;
    END
  END s_axi_rdata_31
  PIN s_axi_rdata_4
    DIRECTION OUTPUT ;
    USE SIGNAL ;
    ANTENNAGATEAREA 0.434700 ;
    ANTENNADIFFAREA 1.137600 ;
    PORT
      LAYER met2 ;
        RECT 42.410 0.000 42.690 0.280 ;
    END
  END s_axi_rdata_4
  PIN s_axi_rdata_5
    DIRECTION OUTPUT ;
    USE SIGNAL ;
    ANTENNAGATEAREA 0.434700 ;
    ANTENNADIFFAREA 1.137600 ;
    PORT
      LAYER met2 ;
        RECT 92.090 0.000 92.370 0.280 ;
    END
  END s_axi_rdata_5
  PIN s_axi_rdata_6
    DIRECTION OUTPUT ;
    USE SIGNAL ;
    ANTENNAGATEAREA 0.434700 ;
    ANTENNADIFFAREA 1.137600 ;
    PORT
      LAYER met2 ;
        RECT 69.090 0.000 69.370 0.280 ;
    END
  END s_axi_rdata_6
  PIN s_axi_rdata_7
    DIRECTION OUTPUT ;
    USE SIGNAL ;
    ANTENNAGATEAREA 0.434700 ;
    ANTENNADIFFAREA 1.137600 ;
    PORT
      LAYER met2 ;
        RECT 66.330 0.000 66.610 0.280 ;
    END
  END s_axi_rdata_7
  PIN s_axi_rdata_8
    DIRECTION OUTPUT ;
    USE SIGNAL ;
    ANTENNAGATEAREA 0.434700 ;
    ANTENNADIFFAREA 1.137600 ;
    PORT
      LAYER met2 ;
        RECT 45.170 0.000 45.450 0.280 ;
    END
  END s_axi_rdata_8
  PIN s_axi_rdata_9
    DIRECTION OUTPUT ;
    USE SIGNAL ;
    ANTENNAGATEAREA 0.434700 ;
    ANTENNADIFFAREA 1.137600 ;
    PORT
      LAYER met3 ;
        RECT 0.000 61.240 0.600 61.840 ;
    END
  END s_axi_rdata_9
  PIN s_axi_rready
    DIRECTION INPUT ;
    USE SIGNAL ;
    ANTENNAGATEAREA 0.647700 ;
    ANTENNADIFFAREA 0.434700 ;
    PORT
      LAYER met3 ;
        RECT 120.920 73.480 121.520 74.080 ;
    END
  END s_axi_rready
  PIN s_axi_rresp_0
    DIRECTION OUTPUT ;
    USE SIGNAL ;
    ANTENNAGATEAREA 0.434700 ;
    ANTENNADIFFAREA 1.137600 ;
    PORT
      LAYER met2 ;
        RECT 82.890 0.000 83.170 0.280 ;
    END
  END s_axi_rresp_0
  PIN s_axi_rresp_1
    DIRECTION OUTPUT ;
    USE SIGNAL ;
    ANTENNAGATEAREA 0.434700 ;
    ANTENNADIFFAREA 1.137600 ;
    PORT
      LAYER met3 ;
        RECT 0.000 50.360 0.600 50.960 ;
    END
  END s_axi_rresp_1
  PIN s_axi_rvalid
    DIRECTION OUTPUT ;
    USE SIGNAL ;
    ANTENNAGATEAREA 0.434700 ;
    ANTENNADIFFAREA 1.137600 ;
    PORT
      LAYER met3 ;
        RECT 120.920 68.040 121.520 68.640 ;
    END
  END s_axi_rvalid
  PIN s_axi_wdata_0
    DIRECTION INPUT ;
    USE SIGNAL ;
    ANTENNAGATEAREA 0.647700 ;
    ANTENNADIFFAREA 0.434700 ;
    PORT
      LAYER met2 ;
        RECT 104.970 131.960 105.250 132.240 ;
    END
  END s_axi_wdata_0
  PIN s_axi_wdata_1
    DIRECTION INPUT ;
    USE SIGNAL ;
    ANTENNAGATEAREA 0.647700 ;
    ANTENNADIFFAREA 0.434700 ;
    PORT
      LAYER met3 ;
        RECT 120.920 89.800 121.520 90.400 ;
    END
  END s_axi_wdata_1
  PIN s_axi_wdata_10
    DIRECTION INPUT ;
    USE SIGNAL ;
    PORT
      LAYER met2 ;
        RECT 46.090 0.000 46.370 0.280 ;
    END
  END s_axi_wdata_10
  PIN s_axi_wdata_11
    DIRECTION INPUT ;
    USE SIGNAL ;
    PORT
      LAYER met2 ;
        RECT 47.010 0.000 47.290 0.280 ;
    END
  END s_axi_wdata_11
  PIN s_axi_wdata_12
    DIRECTION INPUT ;
    USE SIGNAL ;
    PORT
      LAYER met2 ;
        RECT 47.930 0.000 48.210 0.280 ;
    END
  END s_axi_wdata_12
  PIN s_axi_wdata_13
    DIRECTION INPUT ;
    USE SIGNAL ;
    PORT
      LAYER met2 ;
        RECT 48.850 0.000 49.130 0.280 ;
    END
  END s_axi_wdata_13
  PIN s_axi_wdata_14
    DIRECTION INPUT ;
    USE SIGNAL ;
    PORT
      LAYER met2 ;
        RECT 49.770 0.000 50.050 0.280 ;
    END
  END s_axi_wdata_14
  PIN s_axi_wdata_15
    DIRECTION INPUT ;
    USE SIGNAL ;
    PORT
      LAYER met2 ;
        RECT 50.690 0.000 50.970 0.280 ;
    END
  END s_axi_wdata_15
  PIN s_axi_wdata_16
    DIRECTION INPUT ;
    USE SIGNAL ;
    ANTENNAGATEAREA 0.647700 ;
    ANTENNADIFFAREA 0.434700 ;
    PORT
      LAYER met3 ;
        RECT 120.920 63.960 121.520 64.560 ;
    END
  END s_axi_wdata_16
  PIN s_axi_wdata_17
    DIRECTION INPUT ;
    USE SIGNAL ;
    ANTENNAGATEAREA 0.647700 ;
    ANTENNADIFFAREA 0.434700 ;
    PORT
      LAYER met3 ;
        RECT 120.920 77.560 121.520 78.160 ;
    END
  END s_axi_wdata_17
  PIN s_axi_wdata_18
    DIRECTION INPUT ;
    USE SIGNAL ;
    PORT
      LAYER met2 ;
        RECT 53.450 0.000 53.730 0.280 ;
    END
  END s_axi_wdata_18
  PIN s_axi_wdata_19
    DIRECTION INPUT ;
    USE SIGNAL ;
    PORT
      LAYER met2 ;
        RECT 58.970 0.000 59.250 0.280 ;
    END
  END s_axi_wdata_19
  PIN s_axi_wdata_2
    DIRECTION INPUT ;
    USE SIGNAL ;
    ANTENNAGATEAREA 0.647700 ;
    ANTENNADIFFAREA 0.434700 ;
    PORT
      LAYER met3 ;
        RECT 120.920 80.280 121.520 80.880 ;
    END
  END s_axi_wdata_2
  PIN s_axi_wdata_20
    DIRECTION INPUT ;
    USE SIGNAL ;
    PORT
      LAYER met2 ;
        RECT 59.890 0.000 60.170 0.280 ;
    END
  END s_axi_wdata_20
  PIN s_axi_wdata_21
    DIRECTION INPUT ;
    USE SIGNAL ;
    PORT
      LAYER met2 ;
        RECT 60.810 0.000 61.090 0.280 ;
    END
  END s_axi_wdata_21
  PIN s_axi_wdata_22
    DIRECTION INPUT ;
    USE SIGNAL ;
    PORT
      LAYER met2 ;
        RECT 61.730 0.000 62.010 0.280 ;
    END
  END s_axi_wdata_22
  PIN s_axi_wdata_23
    DIRECTION INPUT ;
    USE SIGNAL ;
    PORT
      LAYER met2 ;
        RECT 62.650 0.000 62.930 0.280 ;
    END
  END s_axi_wdata_23
  PIN s_axi_wdata_24
    DIRECTION INPUT ;
    USE SIGNAL ;
    PORT
      LAYER met2 ;
        RECT 63.570 0.000 63.850 0.280 ;
    END
  END s_axi_wdata_24
  PIN s_axi_wdata_25
    DIRECTION INPUT ;
    USE SIGNAL ;
    ANTENNAGATEAREA 0.647700 ;
    ANTENNADIFFAREA 0.434700 ;
    PORT
      LAYER met3 ;
        RECT 120.920 87.080 121.520 87.680 ;
    END
  END s_axi_wdata_25
  PIN s_axi_wdata_26
    DIRECTION INPUT ;
    USE SIGNAL ;
    PORT
      LAYER met2 ;
        RECT 64.490 0.000 64.770 0.280 ;
    END
  END s_axi_wdata_26
  PIN s_axi_wdata_27
    DIRECTION INPUT ;
    USE SIGNAL ;
    PORT
      LAYER met2 ;
        RECT 70.010 0.000 70.290 0.280 ;
    END
  END s_axi_wdata_27
  PIN s_axi_wdata_28
    DIRECTION INPUT ;
    USE SIGNAL ;
    PORT
      LAYER met2 ;
        RECT 70.930 0.000 71.210 0.280 ;
    END
  END s_axi_wdata_28
  PIN s_axi_wdata_29
    DIRECTION INPUT ;
    USE SIGNAL ;
    PORT
      LAYER met2 ;
        RECT 71.850 0.000 72.130 0.280 ;
    END
  END s_axi_wdata_29
  PIN s_axi_wdata_3
    DIRECTION INPUT ;
    USE SIGNAL ;
    ANTENNAGATEAREA 0.647700 ;
    ANTENNADIFFAREA 0.434700 ;
    PORT
      LAYER met2 ;
        RECT 83.810 131.960 84.090 132.240 ;
    END
  END s_axi_wdata_3
  PIN s_axi_wdata_30
    DIRECTION INPUT ;
    USE SIGNAL ;
    PORT
      LAYER met2 ;
        RECT 72.770 0.000 73.050 0.280 ;
    END
  END s_axi_wdata_30
  PIN s_axi_wdata_31
    DIRECTION INPUT ;
    USE SIGNAL ;
    PORT
      LAYER met2 ;
        RECT 73.690 0.000 73.970 0.280 ;
    END
  END s_axi_wdata_31
  PIN s_axi_wdata_4
    DIRECTION INPUT ;
    USE SIGNAL ;
    ANTENNAGATEAREA 0.647700 ;
    ANTENNADIFFAREA 0.434700 ;
    PORT
      LAYER met2 ;
        RECT 82.890 131.960 83.170 132.240 ;
    END
  END s_axi_wdata_4
  PIN s_axi_wdata_5
    DIRECTION INPUT ;
    USE SIGNAL ;
    PORT
      LAYER met2 ;
        RECT 113.250 0.000 113.530 0.280 ;
    END
  END s_axi_wdata_5
  PIN s_axi_wdata_6
    DIRECTION INPUT ;
    USE SIGNAL ;
    PORT
      LAYER met2 ;
        RECT 75.530 0.000 75.810 0.280 ;
    END
  END s_axi_wdata_6
  PIN s_axi_wdata_7
    DIRECTION INPUT ;
    USE SIGNAL ;
    PORT
      LAYER met2 ;
        RECT 76.450 0.000 76.730 0.280 ;
    END
  END s_axi_wdata_7
  PIN s_axi_wdata_8
    DIRECTION INPUT ;
    USE SIGNAL ;
    ANTENNAGATEAREA 0.647700 ;
    ANTENNADIFFAREA 0.434700 ;
    PORT
      LAYER met3 ;
        RECT 120.920 50.360 121.520 50.960 ;
    END
  END s_axi_wdata_8
  PIN s_axi_wdata_9
    DIRECTION INPUT ;
    USE SIGNAL ;
    ANTENNAGATEAREA 0.647700 ;
    ANTENNADIFFAREA 0.434700 ;
    PORT
      LAYER met3 ;
        RECT 120.920 72.120 121.520 72.720 ;
    END
  END s_axi_wdata_9
  PIN s_axi_wready
    DIRECTION OUTPUT ;
    USE SIGNAL ;
    PORT
      LAYER met2 ;
        RECT 77.370 0.000 77.650 0.280 ;
    END
  END s_axi_wready
  PIN s_axi_wstrb_0
    DIRECTION INPUT ;
    USE SIGNAL ;
    ANTENNAGATEAREA 0.647700 ;
    ANTENNADIFFAREA 0.434700 ;
    PORT
      LAYER met3 ;
        RECT 120.920 83.000 121.520 83.600 ;
    END
  END s_axi_wstrb_0
  PIN s_axi_wstrb_1
    DIRECTION INPUT ;
    USE SIGNAL ;
    ANTENNAGATEAREA 0.647700 ;
    ANTENNADIFFAREA 0.434700 ;
    PORT
      LAYER met3 ;
        RECT 120.920 76.200 121.520 76.800 ;
    END
  END s_axi_wstrb_1
  PIN s_axi_wstrb_2
    DIRECTION INPUT ;
    USE SIGNAL ;
    ANTENNAGATEAREA 0.647700 ;
    ANTENNADIFFAREA 0.434700 ;
    PORT
      LAYER met3 ;
        RECT 120.920 78.920 121.520 79.520 ;
    END
  END s_axi_wstrb_2
  PIN s_axi_wstrb_3
    DIRECTION INPUT ;
    USE SIGNAL ;
    ANTENNAGATEAREA 0.647700 ;
    ANTENNADIFFAREA 0.434700 ;
    PORT
      LAYER met3 ;
        RECT 120.920 88.440 121.520 89.040 ;
    END
  END s_axi_wstrb_3
  PIN s_axi_wvalid
    DIRECTION INPUT ;
    USE SIGNAL ;
    ANTENNAGATEAREA 0.647700 ;
    ANTENNADIFFAREA 0.434700 ;
    PORT
      LAYER met2 ;
        RECT 71.850 131.960 72.130 132.240 ;
    END
  END s_axi_wvalid
  PIN soft_reset
    DIRECTION OUTPUT ;
    USE SIGNAL ;
    ANTENNAGATEAREA 0.434700 ;
    ANTENNADIFFAREA 1.137600 ;
    PORT
      LAYER met3 ;
        RECT 0.000 36.760 0.600 37.360 ;
    END
  END soft_reset
  PIN strap_pins_0
    DIRECTION INPUT ;
    USE SIGNAL ;
    PORT
      LAYER met2 ;
        RECT 79.210 0.000 79.490 0.280 ;
    END
  END strap_pins_0
  PIN strap_pins_1
    DIRECTION INPUT ;
    USE SIGNAL ;
    PORT
      LAYER met2 ;
        RECT 81.970 0.000 82.250 0.280 ;
    END
  END strap_pins_1
  PIN strap_pins_10
    DIRECTION INPUT ;
    USE SIGNAL ;
    PORT
      LAYER met2 ;
        RECT 83.810 0.000 84.090 0.280 ;
    END
  END strap_pins_10
  PIN strap_pins_11
    DIRECTION INPUT ;
    USE SIGNAL ;
    PORT
      LAYER met2 ;
        RECT 84.730 0.000 85.010 0.280 ;
    END
  END strap_pins_11
  PIN strap_pins_12
    DIRECTION INPUT ;
    USE SIGNAL ;
    PORT
      LAYER met2 ;
        RECT 85.650 0.000 85.930 0.280 ;
    END
  END strap_pins_12
  PIN strap_pins_13
    DIRECTION INPUT ;
    USE SIGNAL ;
    PORT
      LAYER met2 ;
        RECT 86.570 0.000 86.850 0.280 ;
    END
  END strap_pins_13
  PIN strap_pins_14
    DIRECTION INPUT ;
    USE SIGNAL ;
    PORT
      LAYER met2 ;
        RECT 87.490 0.000 87.770 0.280 ;
    END
  END strap_pins_14
  PIN strap_pins_15
    DIRECTION INPUT ;
    USE SIGNAL ;
    PORT
      LAYER met2 ;
        RECT 88.410 0.000 88.690 0.280 ;
    END
  END strap_pins_15
  PIN strap_pins_16
    DIRECTION INPUT ;
    USE SIGNAL ;
    PORT
      LAYER met2 ;
        RECT 89.330 0.000 89.610 0.280 ;
    END
  END strap_pins_16
  PIN strap_pins_17
    DIRECTION INPUT ;
    USE SIGNAL ;
    PORT
      LAYER met2 ;
        RECT 90.250 0.000 90.530 0.280 ;
    END
  END strap_pins_17
  PIN strap_pins_18
    DIRECTION INPUT ;
    USE SIGNAL ;
    PORT
      LAYER met2 ;
        RECT 91.170 0.000 91.450 0.280 ;
    END
  END strap_pins_18
  PIN strap_pins_19
    DIRECTION INPUT ;
    USE SIGNAL ;
    PORT
      LAYER met2 ;
        RECT 93.010 0.000 93.290 0.280 ;
    END
  END strap_pins_19
  PIN strap_pins_2
    DIRECTION INPUT ;
    USE SIGNAL ;
    PORT
      LAYER met2 ;
        RECT 93.930 0.000 94.210 0.280 ;
    END
  END strap_pins_2
  PIN strap_pins_20
    DIRECTION INPUT ;
    USE SIGNAL ;
    PORT
      LAYER met2 ;
        RECT 94.850 0.000 95.130 0.280 ;
    END
  END strap_pins_20
  PIN strap_pins_21
    DIRECTION INPUT ;
    USE SIGNAL ;
    PORT
      LAYER met2 ;
        RECT 95.770 0.000 96.050 0.280 ;
    END
  END strap_pins_21
  PIN strap_pins_22
    DIRECTION INPUT ;
    USE SIGNAL ;
    PORT
      LAYER met2 ;
        RECT 96.690 0.000 96.970 0.280 ;
    END
  END strap_pins_22
  PIN strap_pins_23
    DIRECTION INPUT ;
    USE SIGNAL ;
    PORT
      LAYER met2 ;
        RECT 97.610 0.000 97.890 0.280 ;
    END
  END strap_pins_23
  PIN strap_pins_24
    DIRECTION INPUT ;
    USE SIGNAL ;
    PORT
      LAYER met2 ;
        RECT 98.530 0.000 98.810 0.280 ;
    END
  END strap_pins_24
  PIN strap_pins_25
    DIRECTION INPUT ;
    USE SIGNAL ;
    PORT
      LAYER met2 ;
        RECT 99.450 0.000 99.730 0.280 ;
    END
  END strap_pins_25
  PIN strap_pins_26
    DIRECTION INPUT ;
    USE SIGNAL ;
    PORT
      LAYER met2 ;
        RECT 100.370 0.000 100.650 0.280 ;
    END
  END strap_pins_26
  PIN strap_pins_27
    DIRECTION INPUT ;
    USE SIGNAL ;
    PORT
      LAYER met2 ;
        RECT 101.290 0.000 101.570 0.280 ;
    END
  END strap_pins_27
  PIN strap_pins_28
    DIRECTION INPUT ;
    USE SIGNAL ;
    PORT
      LAYER met2 ;
        RECT 102.210 0.000 102.490 0.280 ;
    END
  END strap_pins_28
  PIN strap_pins_29
    DIRECTION INPUT ;
    USE SIGNAL ;
    PORT
      LAYER met2 ;
        RECT 103.130 0.000 103.410 0.280 ;
    END
  END strap_pins_29
  PIN strap_pins_3
    DIRECTION INPUT ;
    USE SIGNAL ;
    PORT
      LAYER met2 ;
        RECT 104.050 0.000 104.330 0.280 ;
    END
  END strap_pins_3
  PIN strap_pins_30
    DIRECTION INPUT ;
    USE SIGNAL ;
    PORT
      LAYER met2 ;
        RECT 104.970 0.000 105.250 0.280 ;
    END
  END strap_pins_30
  PIN strap_pins_31
    DIRECTION INPUT ;
    USE SIGNAL ;
    PORT
      LAYER met2 ;
        RECT 105.890 0.000 106.170 0.280 ;
    END
  END strap_pins_31
  PIN strap_pins_4
    DIRECTION INPUT ;
    USE SIGNAL ;
    PORT
      LAYER met2 ;
        RECT 106.810 0.000 107.090 0.280 ;
    END
  END strap_pins_4
  PIN strap_pins_5
    DIRECTION INPUT ;
    USE SIGNAL ;
    PORT
      LAYER met2 ;
        RECT 107.730 0.000 108.010 0.280 ;
    END
  END strap_pins_5
  PIN strap_pins_6
    DIRECTION INPUT ;
    USE SIGNAL ;
    PORT
      LAYER met2 ;
        RECT 108.650 0.000 108.930 0.280 ;
    END
  END strap_pins_6
  PIN strap_pins_7
    DIRECTION INPUT ;
    USE SIGNAL ;
    PORT
      LAYER met2 ;
        RECT 109.570 0.000 109.850 0.280 ;
    END
  END strap_pins_7
  PIN strap_pins_8
    DIRECTION INPUT ;
    USE SIGNAL ;
    PORT
      LAYER met2 ;
        RECT 110.490 0.000 110.770 0.280 ;
    END
  END strap_pins_8
  PIN strap_pins_9
    DIRECTION INPUT ;
    USE SIGNAL ;
    PORT
      LAYER met2 ;
        RECT 111.410 0.000 111.690 0.280 ;
    END
  END strap_pins_9
  PIN sys_clk_ok
    DIRECTION INPUT ;
    USE SIGNAL ;
    PORT
      LAYER met2 ;
        RECT 112.330 0.000 112.610 0.280 ;
    END
  END sys_clk_ok
  PIN wdt_reset
    DIRECTION INPUT ;
    USE SIGNAL ;
    ANTENNAGATEAREA 0.647700 ;
    ANTENNADIFFAREA 0.434700 ;
    PORT
      LAYER met2 ;
        RECT 84.730 131.960 85.010 132.240 ;
    END
  END wdt_reset
  OBS
      LAYER nwell ;
        RECT 5.330 10.795 116.110 119.765 ;
      LAYER li1 ;
        RECT 5.520 10.795 115.920 119.765 ;
      LAYER met1 ;
        RECT 5.130 6.500 119.990 119.920 ;
      LAYER met2 ;
        RECT 5.150 131.680 20.050 132.170 ;
        RECT 20.890 131.680 28.330 132.170 ;
        RECT 29.170 131.680 34.770 132.170 ;
        RECT 35.610 131.680 37.530 132.170 ;
        RECT 38.370 131.680 43.970 132.170 ;
        RECT 44.810 131.680 44.890 132.170 ;
        RECT 45.730 131.680 45.810 132.170 ;
        RECT 46.650 131.680 51.330 132.170 ;
        RECT 52.170 131.680 52.250 132.170 ;
        RECT 53.090 131.680 56.850 132.170 ;
        RECT 57.690 131.680 59.610 132.170 ;
        RECT 60.450 131.680 65.130 132.170 ;
        RECT 65.970 131.680 67.890 132.170 ;
        RECT 68.730 131.680 68.810 132.170 ;
        RECT 69.650 131.680 71.570 132.170 ;
        RECT 72.410 131.680 73.410 132.170 ;
        RECT 74.250 131.680 78.010 132.170 ;
        RECT 78.850 131.680 82.610 132.170 ;
        RECT 83.450 131.680 83.530 132.170 ;
        RECT 84.370 131.680 84.450 132.170 ;
        RECT 85.290 131.680 92.730 132.170 ;
        RECT 93.570 131.680 94.570 132.170 ;
        RECT 95.410 131.680 104.690 132.170 ;
        RECT 105.530 131.680 119.970 132.170 ;
        RECT 5.150 0.560 119.970 131.680 ;
        RECT 5.250 0.280 5.330 0.560 ;
        RECT 6.170 0.280 6.250 0.560 ;
        RECT 7.090 0.280 7.170 0.560 ;
        RECT 8.010 0.280 8.090 0.560 ;
        RECT 8.930 0.280 9.010 0.560 ;
        RECT 9.850 0.280 9.930 0.560 ;
        RECT 10.770 0.280 10.850 0.560 ;
        RECT 11.690 0.280 11.770 0.560 ;
        RECT 12.610 0.280 12.690 0.560 ;
        RECT 13.530 0.280 13.610 0.560 ;
        RECT 14.450 0.280 14.530 0.560 ;
        RECT 15.370 0.280 15.450 0.560 ;
        RECT 16.290 0.280 16.370 0.560 ;
        RECT 17.210 0.280 17.290 0.560 ;
        RECT 18.130 0.280 18.210 0.560 ;
        RECT 19.050 0.280 19.130 0.560 ;
        RECT 19.970 0.280 20.050 0.560 ;
        RECT 20.890 0.280 20.970 0.560 ;
        RECT 21.810 0.280 21.890 0.560 ;
        RECT 22.730 0.280 22.810 0.560 ;
        RECT 23.650 0.280 23.730 0.560 ;
        RECT 24.570 0.280 24.650 0.560 ;
        RECT 25.490 0.280 25.570 0.560 ;
        RECT 26.410 0.280 26.490 0.560 ;
        RECT 27.330 0.280 27.410 0.560 ;
        RECT 28.250 0.280 28.330 0.560 ;
        RECT 29.170 0.280 29.250 0.560 ;
        RECT 30.090 0.280 30.170 0.560 ;
        RECT 31.010 0.280 31.090 0.560 ;
        RECT 31.930 0.280 32.010 0.560 ;
        RECT 32.850 0.280 32.930 0.560 ;
        RECT 33.770 0.280 33.850 0.560 ;
        RECT 34.690 0.280 34.770 0.560 ;
        RECT 35.610 0.280 35.690 0.560 ;
        RECT 36.530 0.280 36.610 0.560 ;
        RECT 37.450 0.280 37.530 0.560 ;
        RECT 38.370 0.280 38.450 0.560 ;
        RECT 39.290 0.280 39.370 0.560 ;
        RECT 40.210 0.280 40.290 0.560 ;
        RECT 41.130 0.280 41.210 0.560 ;
        RECT 42.050 0.280 42.130 0.560 ;
        RECT 42.970 0.280 43.050 0.560 ;
        RECT 43.890 0.280 43.970 0.560 ;
        RECT 44.810 0.280 44.890 0.560 ;
        RECT 45.730 0.280 45.810 0.560 ;
        RECT 46.650 0.280 46.730 0.560 ;
        RECT 47.570 0.280 47.650 0.560 ;
        RECT 48.490 0.280 48.570 0.560 ;
        RECT 49.410 0.280 49.490 0.560 ;
        RECT 50.330 0.280 50.410 0.560 ;
        RECT 51.250 0.280 51.330 0.560 ;
        RECT 52.170 0.280 52.250 0.560 ;
        RECT 53.090 0.280 53.170 0.560 ;
        RECT 54.010 0.280 54.090 0.560 ;
        RECT 54.930 0.280 55.010 0.560 ;
        RECT 55.850 0.280 55.930 0.560 ;
        RECT 56.770 0.280 56.850 0.560 ;
        RECT 57.690 0.280 57.770 0.560 ;
        RECT 58.610 0.280 58.690 0.560 ;
        RECT 59.530 0.280 59.610 0.560 ;
        RECT 60.450 0.280 60.530 0.560 ;
        RECT 61.370 0.280 61.450 0.560 ;
        RECT 62.290 0.280 62.370 0.560 ;
        RECT 63.210 0.280 63.290 0.560 ;
        RECT 64.130 0.280 64.210 0.560 ;
        RECT 65.050 0.280 65.130 0.560 ;
        RECT 65.970 0.280 66.050 0.560 ;
        RECT 66.890 0.280 66.970 0.560 ;
        RECT 67.810 0.280 67.890 0.560 ;
        RECT 68.730 0.280 68.810 0.560 ;
        RECT 69.650 0.280 69.730 0.560 ;
        RECT 70.570 0.280 70.650 0.560 ;
        RECT 71.490 0.280 71.570 0.560 ;
        RECT 72.410 0.280 72.490 0.560 ;
        RECT 73.330 0.280 73.410 0.560 ;
        RECT 74.250 0.280 74.330 0.560 ;
        RECT 75.170 0.280 75.250 0.560 ;
        RECT 76.090 0.280 76.170 0.560 ;
        RECT 77.010 0.280 77.090 0.560 ;
        RECT 77.930 0.280 78.010 0.560 ;
        RECT 78.850 0.280 78.930 0.560 ;
        RECT 79.770 0.280 79.850 0.560 ;
        RECT 80.690 0.280 80.770 0.560 ;
        RECT 81.610 0.280 81.690 0.560 ;
        RECT 82.530 0.280 82.610 0.560 ;
        RECT 83.450 0.280 83.530 0.560 ;
        RECT 84.370 0.280 84.450 0.560 ;
        RECT 85.290 0.280 85.370 0.560 ;
        RECT 86.210 0.280 86.290 0.560 ;
        RECT 87.130 0.280 87.210 0.560 ;
        RECT 88.050 0.280 88.130 0.560 ;
        RECT 88.970 0.280 89.050 0.560 ;
        RECT 89.890 0.280 89.970 0.560 ;
        RECT 90.810 0.280 90.890 0.560 ;
        RECT 91.730 0.280 91.810 0.560 ;
        RECT 92.650 0.280 92.730 0.560 ;
        RECT 93.570 0.280 93.650 0.560 ;
        RECT 94.490 0.280 94.570 0.560 ;
        RECT 95.410 0.280 95.490 0.560 ;
        RECT 96.330 0.280 96.410 0.560 ;
        RECT 97.250 0.280 97.330 0.560 ;
        RECT 98.170 0.280 98.250 0.560 ;
        RECT 99.090 0.280 99.170 0.560 ;
        RECT 100.010 0.280 100.090 0.560 ;
        RECT 100.930 0.280 101.010 0.560 ;
        RECT 101.850 0.280 101.930 0.560 ;
        RECT 102.770 0.280 102.850 0.560 ;
        RECT 103.690 0.280 103.770 0.560 ;
        RECT 104.610 0.280 104.690 0.560 ;
        RECT 105.530 0.280 105.610 0.560 ;
        RECT 106.450 0.280 106.530 0.560 ;
        RECT 107.370 0.280 107.450 0.560 ;
        RECT 108.290 0.280 108.370 0.560 ;
        RECT 109.210 0.280 109.290 0.560 ;
        RECT 110.130 0.280 110.210 0.560 ;
        RECT 111.050 0.280 111.130 0.560 ;
        RECT 111.970 0.280 112.050 0.560 ;
        RECT 112.890 0.280 112.970 0.560 ;
        RECT 113.810 0.280 119.970 0.560 ;
      LAYER met3 ;
        RECT 0.600 115.280 120.920 119.845 ;
        RECT 1.000 113.880 120.920 115.280 ;
        RECT 0.600 112.560 120.920 113.880 ;
        RECT 1.000 111.160 120.920 112.560 ;
        RECT 0.600 101.680 120.920 111.160 ;
        RECT 1.000 97.560 120.920 101.680 ;
        RECT 0.600 96.240 120.920 97.560 ;
        RECT 1.000 94.840 120.920 96.240 ;
        RECT 0.600 90.800 120.920 94.840 ;
        RECT 0.600 88.080 120.520 90.800 ;
        RECT 1.000 83.960 120.520 88.080 ;
        RECT 0.600 82.600 120.520 83.960 ;
        RECT 0.600 81.280 120.920 82.600 ;
        RECT 1.000 78.520 120.520 81.280 ;
        RECT 0.600 77.200 120.520 78.520 ;
        RECT 1.000 75.800 120.520 77.200 ;
        RECT 1.000 74.480 120.920 75.800 ;
        RECT 1.000 69.000 120.520 74.480 ;
        RECT 0.600 66.280 120.520 69.000 ;
        RECT 0.600 64.960 120.920 66.280 ;
        RECT 1.000 63.560 120.520 64.960 ;
        RECT 1.000 62.240 120.920 63.560 ;
        RECT 1.000 54.040 120.520 62.240 ;
        RECT 1.000 51.360 120.920 54.040 ;
        RECT 1.000 49.960 120.520 51.360 ;
        RECT 1.000 48.640 120.920 49.960 ;
        RECT 1.000 35.000 120.520 48.640 ;
        RECT 0.600 33.640 120.520 35.000 ;
        RECT 0.600 30.960 120.920 33.640 ;
        RECT 0.600 29.560 120.520 30.960 ;
        RECT 0.600 16.000 120.920 29.560 ;
        RECT 0.600 14.600 120.520 16.000 ;
        RECT 0.600 10.715 120.920 14.600 ;
  END
END sys_ctrl
END LIBRARY

